VERSION 5.7 ;
  NOWIREEXTENSIONATPIN ON ;
  DIVIDERCHAR "/" ;
  BUSBITCHARS "[]" ;
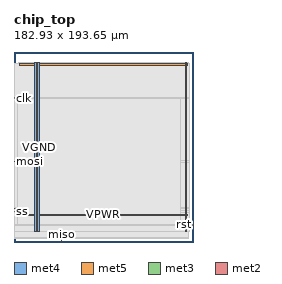
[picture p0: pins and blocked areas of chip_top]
MACRO chip_top
  CLASS BLOCK ;
  FOREIGN chip_top ;
  ORIGIN 0.000 0.000 ;
  SIZE 182.930 BY 193.650 ;
  PIN VGND
    DIRECTION INOUT ;
    USE GROUND ;
    PORT
      LAYER met4 ;
        RECT 24.340 10.640 25.940 182.480 ;
    END
  END VGND
  PIN VPWR
    DIRECTION INOUT ;
    USE POWER ;
    PORT
      LAYER met4 ;
        RECT 21.040 10.640 22.640 182.480 ;
    END
    PORT
      LAYER met4 ;
        RECT 174.640 10.640 176.240 182.480 ;
    END
    PORT
      LAYER met5 ;
        RECT 5.280 26.730 177.340 28.330 ;
    END
    PORT
      LAYER met5 ;
        RECT 5.280 179.910 177.340 181.510 ;
    END
  END VPWR
  PIN clk
    DIRECTION INPUT ;
    USE SIGNAL ;
    ANTENNAGATEAREA 0.852000 ;
    PORT
      LAYER met3 ;
        RECT 0.000 146.240 4.000 146.840 ;
    END
  END clk
  PIN miso
    DIRECTION OUTPUT ;
    USE SIGNAL ;
    ANTENNADIFFAREA 1.782000 ;
    PORT
      LAYER met2 ;
        RECT 48.390 0.000 48.670 4.000 ;
    END
  END miso
  PIN mosi
    DIRECTION INPUT ;
    USE SIGNAL ;
    ANTENNAGATEAREA 0.196500 ;
    PORT
      LAYER met3 ;
        RECT 0.000 81.640 4.000 82.240 ;
    END
  END mosi
  PIN rst
    DIRECTION INPUT ;
    USE SIGNAL ;
    ANTENNAGATEAREA 0.852000 ;
    PORT
      LAYER met3 ;
        RECT 178.930 17.040 182.930 17.640 ;
    END
  END rst
  PIN sclk
    DIRECTION INPUT ;
    USE SIGNAL ;
    ANTENNAGATEAREA 0.126000 ;
    PORT
      LAYER met3 ;
        RECT 0.000 34.040 4.000 34.640 ;
    END
  END sclk
  PIN ss
    DIRECTION INPUT ;
    USE SIGNAL ;
    ANTENNAGATEAREA 0.196500 ;
    PORT
      LAYER met3 ;
        RECT 0.000 30.640 4.000 31.240 ;
    END
  END ss
  OBS
      LAYER nwell ;
        RECT 5.330 10.795 177.290 182.430 ;
      LAYER li1 ;
        RECT 5.520 10.795 177.100 182.325 ;
      LAYER met1 ;
        RECT 4.210 10.640 177.950 182.480 ;
      LAYER met2 ;
        RECT 0.550 4.280 177.920 182.425 ;
        RECT 0.550 4.000 48.110 4.280 ;
        RECT 48.950 4.000 177.920 4.280 ;
      LAYER met3 ;
        RECT 0.525 147.240 178.930 182.405 ;
        RECT 4.400 145.840 178.930 147.240 ;
        RECT 0.525 82.640 178.930 145.840 ;
        RECT 4.400 81.240 178.930 82.640 ;
        RECT 0.525 35.040 178.930 81.240 ;
        RECT 4.400 33.640 178.930 35.040 ;
        RECT 0.525 31.640 178.930 33.640 ;
        RECT 4.400 30.240 178.930 31.640 ;
        RECT 0.525 18.040 178.930 30.240 ;
        RECT 0.525 16.640 178.530 18.040 ;
        RECT 0.525 10.715 178.930 16.640 ;
      LAYER met4 ;
        RECT 3.975 17.855 20.640 146.705 ;
        RECT 23.040 17.855 23.940 146.705 ;
        RECT 26.340 17.855 169.905 146.705 ;
  END
END chip_top
END LIBRARY

